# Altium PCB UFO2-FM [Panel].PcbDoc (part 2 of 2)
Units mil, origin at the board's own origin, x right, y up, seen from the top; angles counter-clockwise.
Board outline 9805 x 6875 mil, 2 copper layers (Top Layer, Bottom Layer), stack 63.824 mil thick; 0 components, 51 nets, 492 pads, 0 vias.

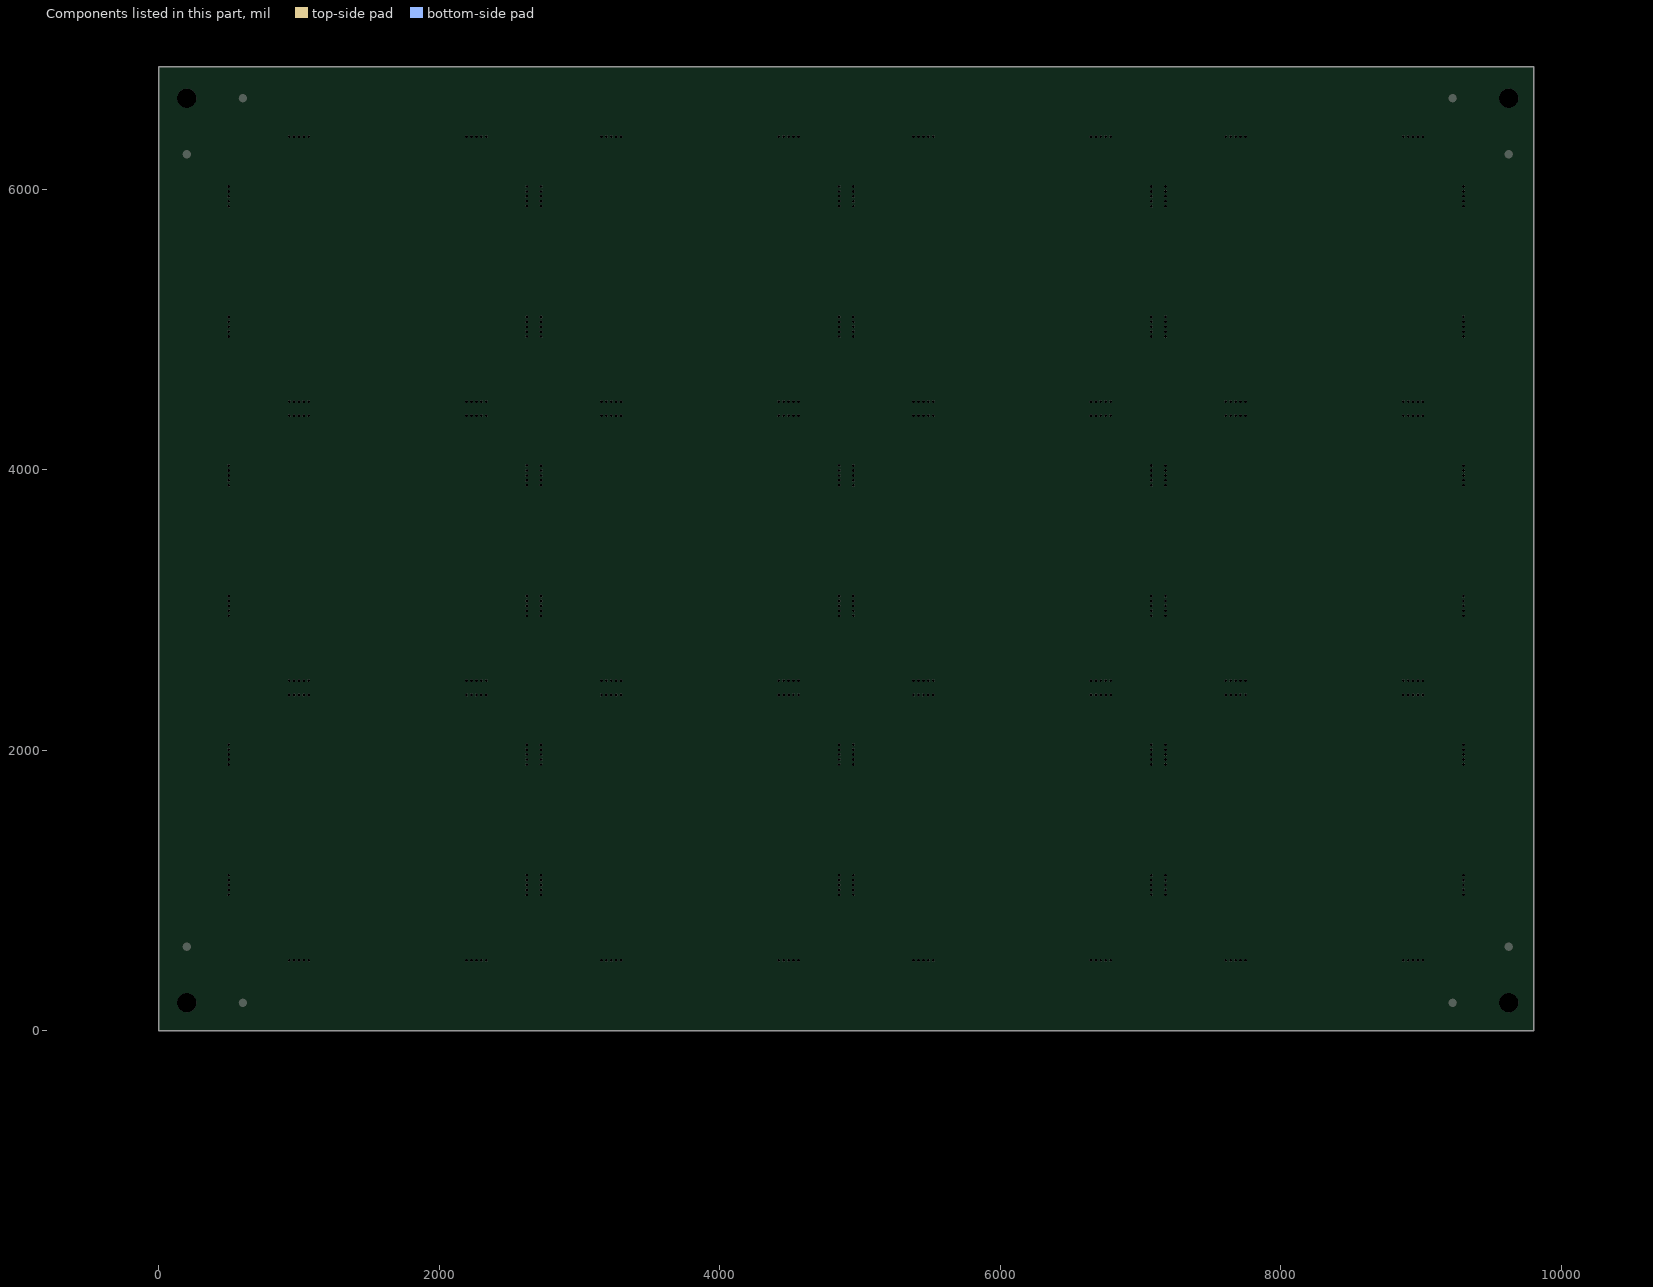
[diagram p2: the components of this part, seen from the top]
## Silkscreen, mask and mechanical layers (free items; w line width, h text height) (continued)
Drill Drawing:
  circle w4.92: c6399.29,-2325.03 r118.11
  circle w4.92: c6399.29,-2325.03 r39.37
  region: 0,0 -78.74,-39.37 -39.37,-78.74
  lines w7.87: -1183.39,-2506.13 -1183.39,8911.19 14958.35,8911.19 14958.35,-2506.13 ; -1182.87,-2505.3 -1182.87,-2522.04 -1160.24,-2522.04 ; -1159.76,-2521.88 14958,-2521.88 ; -669.29,-275.59 -275.59,-275.59 0,0 ; 3816.24,-2325.03 6217.81,-2325.03 ; 3816.61,-2506.13 3816.61,-1325.03 6218.19,-1325.03 ; 3817,-2128.18 6241.81,-2128.18 6849,-2129.05 10651.26,-2128.18 ; 4564.27,-2521.88 4564.27,-2325.03 ; 5391.04,-2521.88 5391.04,-2325.03 ; 6218.19,-2327.05 6218.19,-1325.03 ; 6218.19,-1718.73 6848.11,-1718.73 10627.64,-1718.73 ; 6261.5,-2325.03 6812.68,-2325.03 ; 6399.29,-2462.82 6399.29,-2187.23 ; 6848.11,-2326.05 6848.11,-1325.03 ; 6848.11,-1915.58 10627.64,-1915.58 ; 6848.11,-1521.88 10627.64,-1521.88 ; 7478.03,-2506.13 7478.03,-1325.03 ; 8107,-2325.03 8761.5,-2325.03 9391.42,-2325.03 10021.34,-2325.03 10628,-2325.03 ; 8107.57,-2521.88 8107.57,-2325.03 7477.65,-2325.03 6847.73,-2325.03 ; 8107.95,-2506.13 8107.95,-1325.03 ; 8737.87,-2506.13 8737.87,-1325.03 ; 9367.8,-2506.13 9367.8,-1325.03 ; 9997.72,-2506.13 9997.72,-1325.03 ; 10627.26,-2521.88 14957.97,-2521.88 14957.97,-2128.18 10627.26,-2128.18 ; 10627.26,-2325.03 14957.97,-2325.03 ; 10627.64,-2521.05 10627.64,-1325.03 ; 10627.64,446.63 14958.35,446.63 ; 10627.64,1196.85 14958.35,1196.85 ; 10627.64,1393.7 14958.35,1393.7 ; 10628.11,1996.63 14958.82,1996.63 ; 10628.11,2193.48 14958.82,2193.48 ; 10628.11,2385.61 10628.47,2384.24 10628.47,1801.98 ; 10628.11,2580.88 14958.82,2580.88 ; 10628.11,2777.73 14958.82,2777.73 14958.82,1801.98 ; 10628.11,2974.58 14958.82,2974.58 ; 10628.11,3171.43 14958.82,3171.43 ; 10628.11,3368.28 14958.82,3368.28 ; 10628.47,1800 14958.35,1800 14958.35,1996.87 ; 10628.47,1800.85 10628.47,1963.85 10628.47,1964.85 ; 10628.47,2376.79 10628.47,3171.65 10628.11,3173.01 10628.11,3565.13 14958.82,3565.13 14958.82,2376.79 ; 10942.6,1006.13 10942.6,1393.7 ; 10943.07,1801.98 10943.07,3370.88 ; 10981.97,52.93 10981.97,643.48 ; 11335.92,-2521.88 11335.92,-2128.18 ; 11572.52,-1128.18 11572.52,-340.78 ; 12478.03,1006.13 12478.03,1393.7 ; 12478.5,1801.98 12478.5,2580.88 ; 12478.5,2376.79 12478.5,3368.28 ; 12596.14,643.48 12674.88,643.48 12674.88,52.93 ; 13501.28,-2521.88 13501.28,-2128.18 ; 14013.09,-2521.88 14013.09,-2128.18 ; 14092.2,1000.22 14092.2,1393.7 ; 14092.68,1801.98 14092.68,2580.88 ; 14092.68,2376.79 14092.68,3368.28 ; 14485.9,1004.16 14485.9,1393.7 ; 14486.38,1801.98 14486.38,2580.88 ; 14486.38,2376.79 14486.38,3368.28 ; 14958.35,-1325.03 10627.64,-1325.03 ; 14958.35,-537.63 10627.64,-537.63 ; 14958.35,52.93 10627.64,52.93 10627.64,249.78 ; 14958.35,249.78 10627.64,249.78 ; 14958.35,643.48 10627.64,643.48 ; 14958.35,840.33 10627.64,840.33 10627.64,643.48 ; 14958.35,1000 10630.67,1000 10627.64,1003.03 10627.64,1590.55 14958.35,1590.55 14958.35,1000.22 ; 6217.81,-2325.03 6217.81,-2521.88 6217.81,-2325.03 ; 6218.19,-1325.03 6848.11,-1325.03 ; 6847.73,-2521.88 6847.73,-2325.03 ; 6847.73,-2521.88 6847.73,-2325.03 ; 6847.73,-2521.88 6847.73,-2325.03 ; 6848.11,-1325.03 10627.64,-1325.03 ; 10627.64,-1128.18 14958.35,-1128.18 10627.64,-1128.18 ; 10627.64,-1128.18 10627.64,-143.93 ; 10627.64,-1128.18 10627.64,-931.33 ; 10627.64,-931.33 10627.64,-537.63 ; 10627.64,-931.33 10627.64,-734.48 14958.35,-734.48 14958.35,-931.33 10627.64,-931.33 ; 10627.64,-537.63 10627.64,-340.78 ; 10627.64,-340.78 14958.35,-340.78 10627.64,-340.78 ; 10627.64,-340.78 10627.64,-143.93 ; 10627.64,-143.93 14958.35,-143.93 10627.64,-143.93 ; 10627.64,249.78 10627.64,643.48 ; 10628.11,2384.03 14958.82,2384.03 ; 10628.11,2384.03 14958.82,2384.03 ; 10628.11,2384.03 14958.82,2384.03 ; 10628.11,2384.03 14958.82,2384.03 ; 6556.77,-2364.4 6556.77,-2325.03 6556.77,-2285.66 6792.99,-2206.92 6792.99,-2443.14 6556.77,-2364.4
  text ".Legend" at 10400,3800 h78.74
  text "LAYER BUILD DATA" at 11887.95,3447.02 h118.11
  text "SHT" at 10706.85,3250.17 h98.43
  text "DESCRIPTION" at 11021.81,3250.17 h98.43
  text "PLOTFILE" at 12557.24,3250.17 h98.43
  text "EXT" at 14210.79,3250.17 h98.43
  text "P/N" at 14643.86,3250.17 h98.43
  text "GD1" at 14176.42,3059.35 h98.43
  text "1" at 10785.59,3053.32 h98.43
  text "CUTTING & DRILLING DRAWING" at 11021.81,3053.32 h98.43
  text ".PCB_Plot File" at 12557.24,3053.32 h98.43
  text "-" at 14643.86,3053.32 h98.43
  text "GTO" at 14176.42,2862.5 h98.43
  text "2" at 10785.59,2856.47 h98.43
  text "TOP SIDE LEGEND" at 11021.81,2856.47 h98.43
  text ".PCB_Plot File" at 12557.24,2856.47 h98.43
  text "POS" at 14643.86,2856.47 h98.43
  text "GTS" at 14176.42,2665.65 h98.43
  text "3" at 10785.59,2659.62 h98.43
  text "TOP SIDE SOLDER MASK" at 11021.81,2659.62 h98.43
  text ".PCB_Plot File" at 12557.24,2659.62 h98.43
  text "NEG" at 14643.86,2659.62 h98.43
  text "GTL" at 14176.42,2468.8 h98.43
  text "4" at 10785.59,2462.77 h98.43
  text "TOP SIDE" at 11021.81,2462.77 h98.43
  text ".PCB_Plot File" at 12557.24,2462.77 h98.43
  text "POS" at 14643.86,2462.77 h98.43
  text "GBL" at 14176.42,2278.25 h98.43
  text "BOTTOM SIDE" at 11021.81,2272.22 h98.43
  text ".PCB_Plot File" at 12557.24,2272.22 h98.43
  text "POS" at 14643.86,2272.22 h98.43
  text "5" at 10785.59,2265.92 h98.43
  text "GBS" at 14176.42,2081.4 h98.43
  text "BOTTOM SIDE SOLDER MASK" at 11021.81,2075.37 h98.43
  text ".PCB_Plot File" at 12557.24,2075.37 h98.43
  text "NEG" at 14643.86,2075.37 h98.43
  text "6" at 10785.59,2069.07 h98.43
  text "GBO" at 14176.78,1884.77 h98.43
  text "7" at 10785.95,1878.74 h98.43
  text "BOTTOM SIDE LEGEND" at 11022.17,1878.74 h98.43
  text ".PCB_Plot File" at 12557.61,1878.74 h98.43
  text "POS" at 14644.22,1878.74 h98.43
  text "SOLDER STENCIL DATA" at 11887.48,1472.44 h118.11
  text "SHT" at 10706.38,1275.59 h98.43
  text "DESCRIPTION" at 11021.34,1275.59 h98.43
  text "PLOTFILE" at 12556.77,1275.59 h98.43
  text "EXT" at 14210.31,1275.59 h98.43
  text "P/N" at 14643.38,1275.59 h98.43
  text "GTP" at 14175.94,1084.77 h98.43
  text "1" at 10785.12,1078.74 h98.43
  text "TOP SIDE SOLDER STENCIL" at 11021.34,1078.74 h98.43
  text ".PCB_Plot File" at 12556.77,1078.74 h98.43
  text "POS" at 14643.38,1078.74 h98.43
  text "MATERIAL" at 12320.55,722.22 h118.11
  text "ITEM" at 10706.38,525.37 h98.43
  text "FINAL THICKNESS" at 11336.3,525.37 h98.43
  text "MATERIAL" at 13226.06,525.37 h98.43
  text "Cu" at 10706.38,328.52 h98.43
  text "COPPER CLAD" at 13226.06,328.52 h98.43
  text ".Spec_Cu Thickness" at 11337.13,327.96 h98.43
  text "(ON ALL LAYERS)" at 11607.13,327.96 h98.43
  text "PCB" at 10706.38,131.67 h98.43
  text ".Spec_PCB Thickness" at 11336.3,131.67 h98.43
  text "NEMA FR4" at 13226.06,131.67 h98.43
  text "FINISH" at 12281.18,-262.03 h118.11
  text "NC DRILL" at -669.29,-354.33 h78.74
  text "ORIGIN" at -669.29,-433.07 h78.74
  text "ITEM" at 10745.75,-458.89 h98.43
  text "DESCRIPTION" at 11690.63,-458.89 h98.43
  text "X = 0 ; Y = 0" at -669.29,-511.81 h78.74
  text "PCB" at 10745.75,-655.74 h98.43
  text "IMMERSION GOLD" at 11690.63,-655.74 h98.43
  text "SOLDER MASK" at 10745.75,-852.59 h98.43
  text ".Spec_Solder Mask" at 11687.13,-858.62 h98.43
  text "PHOTO-IMAGEABLE" at 12027.13,-858.62 h98.43
  text "LEGEND" at 10745.75,-1049.44 h98.43
  text ".Spec_Silkscreen" at 11690.63,-1049.44 h98.43
  text "TITLE" at 10706.38,-1443.14 h98.43
  text "UNITS" at 6415.04,-1482.51 h98.43
  text "METRIC" at 6375.67,-1600.62 h98.43
  text "AGRIGEL" at 3983.69,-1696.05 h393.7
  text ".PCB_TITLE" at 10942.6,-1718.73 h196.85
  text "(CUTTING & DRILLING DRAWING)" at 10981.97,-1836.84 h98.43
  text "SCALE" at 6375.67,-1876.21 h98.43
  text "N/A" at 6454.41,-1994.32 h98.43
  text "TOLERANCES UNLESS OTHERWISE STATED" at 4092.2,-2230.54 h98.43
  text ".PCB_Drawn" at 7005.59,-2230.54 h98.43
  text ".PCB_Checked" at 7596.14,-2230.54 h98.43
  text ".PCB_Approved" at 8226.06,-2230.54 h98.43
  text ".PRINT_DATE" at 8855.98,-2230.54 h98.43
  text ".PCB_DocRevision" at 9407.17,-2230.54 h98.43
  text ".PCB_ECRNo" at 10155.2,-2230.54 h98.43
  text "DWG NUMBER" at 10643.01,-2230.54 h98.43
  text ".PCB_Drawing Number" at 11391.04,-2230.54 h98.43
  text "PCB VER" at 13517.02,-2230.54 h98.43
  text "SHEET NO." at 14304.42,-2230.54 h98.43
  text "1 = +/-0.2" at 3989.46,-2427.39 h98.43
  text "1.0 = +/-0.1" at 4737.5,-2427.39 h98.43
  text "1.00 = +/-0.5" at 5524.9,-2427.39 h98.43
  text "DRAWN" at 6981.59,-2427.39 h98.43
  text "CHECKED" at 7572.14,-2427.39 h98.43
  text "APPROVED" at 8186.69,-2427.39 h98.43
  text "DATE" at 8934.72,-2427.39 h98.43
  text "DOC REV." at 9485.91,-2427.39 h98.43
  text "ECR NO." at 10155.2,-2427.39 h98.43
  text "SOURCE" at 10643.01,-2427.39 h98.43
  text ".Pcb_File_Name_No_Path" at 11391.04,-2427.39 h98.43
  text ".Version" at 13595.76,-2427.39 h98.43
  text "SHEET" at 14068.2,-2427.39 h98.43
  text "1" at 14422.54,-2427.39 h98.43
  text "OF" at 14540.65,-2427.39 h98.43
  text "7" at 14737.5,-2427.39 h98.43

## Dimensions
0,0 to 9805,0 on Drill Drawing
0,6875 to 0,0 on Drill Drawing

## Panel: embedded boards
"UFO2-FM.PcbDoc" at 499.22,504.22, 3 rows x 4 columns, spacing 1990 x 2225.98, rotation 0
